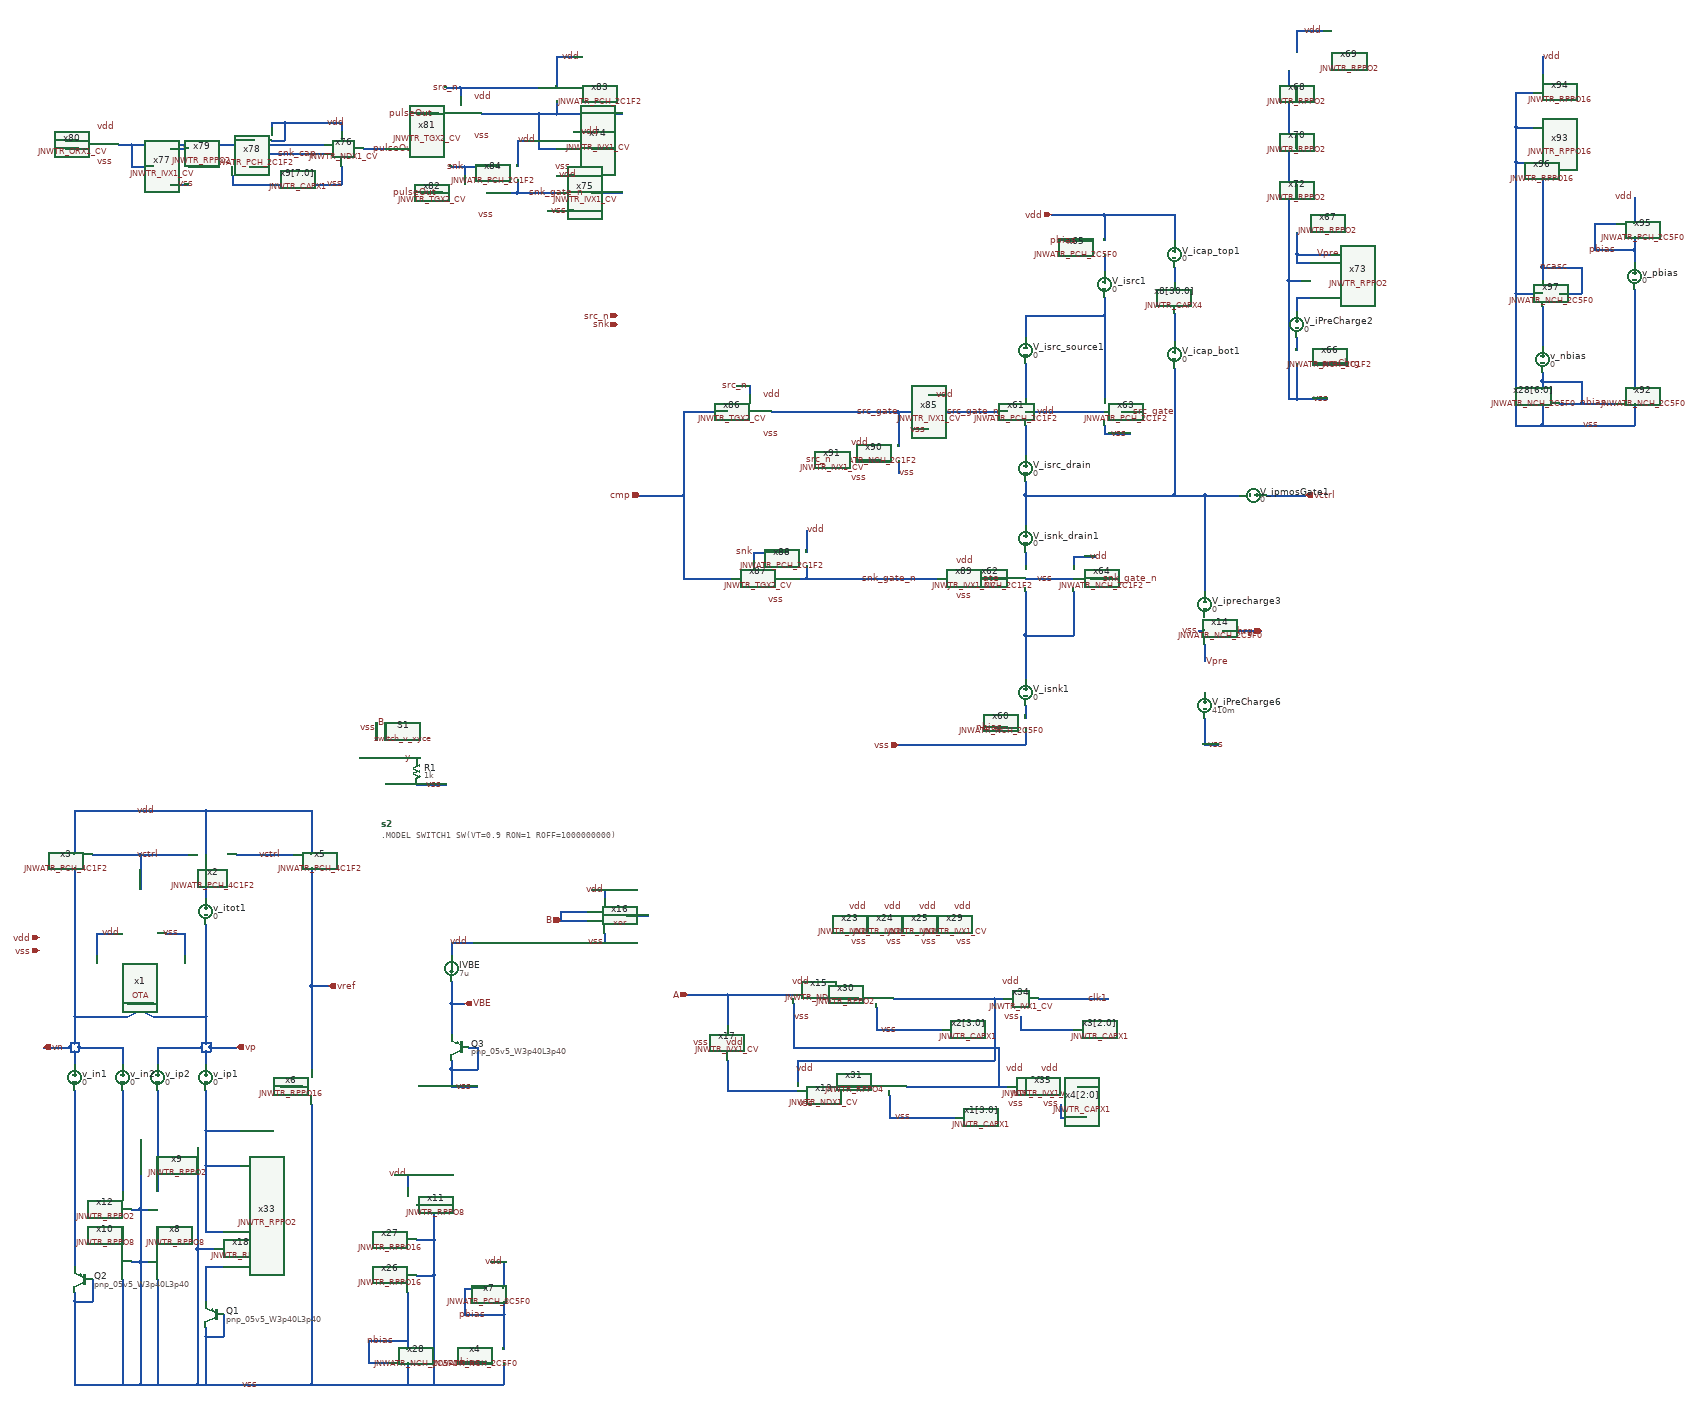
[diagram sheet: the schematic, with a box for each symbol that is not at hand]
v {xschem version=3.4.6 file_version=1.2}
G {}
K {}
V {}
S {}
E {}
N 870 -120 960 -120 {
lab=nbias}
N 960 -120 960 -100 {
lab=nbias}
N 1180 -210 1180 -180 {
lab=pbias}
N 1090 -180 1180 -180 {
lab=pbias}
N 1090 -240 1090 -180 {
lab=pbias}
N 1090 -240 1140 -240 {
lab=pbias}
N 1180 -300 1180 -240 {
lab=vdd}
N 960 -70 960 -20 {
lab=vss}
N 930 -500 960 -500 {
lab=vdd}
N 1020 -270 1020 -20 {
lab=vss}
N 980 -270 1020 -270 {
lab=vss}
N 1020 -350 1020 -270 {
lab=vss}
N 980 -350 1020 -350 {
lab=vss}
N 1020 -430 1020 -350 {
lab=vss}
N 980 -430 1020 -430 {
lab=vss}
N 960 -500 960 -470 {
lab=vdd}
N 1090 -70 1140 -70 {
lab=nbias}
N 1020 -20 1180 -20 {
lab=vss}
N 1150 -300 1180 -300 {
lab=vdd}
N 870 -120 870 -70 {
lab=nbias}
N 870 -70 920 -70 {
lab=nbias}
N 1180 -70 1180 -20 {
lab=vss}
N 1180 -180 1180 -100 {
lab=pbias}
N 960 -230 960 -120 {
lab=nbias}
N 490 -790 490 -780 {
lab=vp}
N 500 -800 510 -800 {
lab=vp}
N 210 -790 210 -780 {
lab=vn}
N 200 -800 210 -800 {
lab=vn}
N 510 -790 510 -780 {
lab=vp}
N 210 -800 210 -790 {
lab=vn}
N 490 -800 490 -790 {
lab=vp}
N 390 -790 490 -790 {
lab=vp}
N 200 -780 210 -780 {
lab=vn}
N 210 -790 310 -790 {
lab=vn}
N 190 -790 190 -780 {
lab=vn}
N 240 -260 240 -210 {
lab=vss}
N 200 -210 240 -210 {
lab=vss}
N 200 -230 200 -210 {
lab=vss}
N 540 -180 540 -130 {
lab=vss}
N 500 -130 540 -130 {
lab=vss}
N 500 -150 500 -130 {
lab=vss}
N 500 -780 510 -780 {
lab=vp}
N 380 -860 500 -860 {
lab=vp}
N 200 -860 200 -800 {
lab=vn}
N 190 -800 200 -800 {
lab=vn}
N 500 -860 500 -800 {
lab=vp}
N 490 -800 500 -800 {
lab=vp}
N 200 -1200 200 -860 {
lab=vn}
N 200 -860 320 -860 {
lab=vn}
N 350 -1230 350 -1150 {
lab=vctrl}
N 350 -1230 460 -1230 {
lab=vctrl}
N 240 -1230 350 -1230 {
lab=vctrl}
N 200 -1330 200 -1230 {
lab=vdd}
N 200 -1330 500 -1330 {
lab=vdd}
N 740 -1330 740 -1230 {
lab=vdd}
N 500 -1330 740 -1330 {
lab=vdd}
N 500 -1330 500 -1230 {
lab=vdd}
N 740 -930 740 -740 {
lab=vref}
N 510 -790 570 -790 {
lab=vp}
N 510 -800 510 -790 {
lab=vp}
N 130 -790 190 -790 {
lab=vn}
N 190 -800 190 -790 {
lab=vn}
N 740 -930 780 -930 {
lab=vref}
N 740 -1200 740 -930 {
lab=vref}
N 570 -1230 700 -1230 {
lab=vctrl}
N 500 -130 500 -20 {
lab=vss}
N 200 -210 200 -20 {
lab=vss}
N 500 -20 740 -20 {
lab=vss}
N 670 -700 720 -700 {
lab=vss}
N 740 -660 740 -20 {
lab=vss}
N 960 -20 1020 -20 {
lab=vss}
N 740 -20 960 -20 {
lab=vss}
N 480 -20 500 -20 {
lab=vss}
N 500 -1200 500 -1130 {
lab=#net1}
N 500 -780 500 -750 {
lab=vp}
N 490 -780 500 -780 {
lab=vp}
N 390 -790 390 -750 {
lab=vp}
N 200 -780 200 -750 {
lab=vn}
N 190 -780 200 -780 {
lab=vn}
N 200 -690 200 -290 {
lab=#net2}
N 310 -790 310 -750 {
lab=vn}
N 1060 -890 1060 -820 {
lab=VBE}
N 1060 -740 1060 -700 {
lab=vss}
N 1060 -700 1120 -700 {
lab=vss}
N 1060 -1030 1060 -1000 {
lab=vdd}
N 1060 -1030 1110 -1030 {
lab=vdd}
N 1060 -890 1090 -890 {
lab=VBE}
N 1060 -940 1060 -890 {
lab=VBE}
N 1100 -790 1120 -790 {
lab=vss}
N 1120 -790 1120 -740 {
lab=vss}
N 1060 -740 1120 -740 {
lab=vss}
N 1060 -760 1060 -740 {
lab=vss}
N 1310 -1100 1370 -1100 {
lab=B}
N 1310 -1080 1370 -1080 {
lab=B}
N 1410 -1150 1410 -1130 {
lab=vdd}
N 1380 -1150 1410 -1150 {
lab=vdd}
N 1410 -1050 1410 -1030 {
lab=vss}
N 1380 -1030 1410 -1030 {
lab=vss}
N 1460 -1090 1510 -1090 {
lab=#net3}
N 500 -520 500 -370 {
lab=#net4}
N 350 -300 370 -300 {
lab=vss}
N 330 -300 350 -300 {
lab=vss}
N 350 -420 370 -420 {
lab=vss}
N 330 -420 350 -420 {
lab=vss}
N 350 -420 350 -300 {
lab=vss}
N 350 -580 350 -420 {
lab=vss}
N 500 -520 580 -520 {
lab=#net4}
N 500 -600 580 -600 {
lab=#net4}
N 310 -690 310 -460 {
lab=#net5}
N 390 -690 390 -460 {
lab=#net6}
N 500 -690 500 -600 {
lab=#net4}
N 500 -290 500 -210 {
lab=#net7}
N 480 -330 480 -20 {
lab=vss}
N 390 -20 480 -20 {
lab=vss}
N 350 -300 350 -20 {
lab=vss}
N 310 -260 310 -20 {
lab=vss}
N 200 -20 310 -20 {
lab=vss}
N 390 -260 390 -20 {
lab=vss}
N 350 -20 390 -20 {
lab=vss}
N 310 -20 350 -20 {
lab=vss}
N 500 -1070 500 -860 {
lab=vp}
N 320 -860 380 -890 {
lab=vn}
N 320 -890 380 -860 {
lab=vp}
N 250 -1050 250 -1000 {
lab=vdd}
N 250 -1050 290 -1050 {
lab=vdd}
N 450 -1050 450 -1000 {
lab=vss}
N 410 -1050 450 -1050 {
lab=vss}
N 940 -1450 980 -1450 {
lab=y}
N 890 -1530 890 -1490 {
lab=vss}
N 910 -1530 910 -1490 {
lab=B}
N 850 -1450 880 -1450 {
lab=#net8}
N 980 -1390 1050 -1390 {
lab=vss}
N 1690 -760 1690 -690 {
lab=#net9}
N 1690 -690 1850 -690 {
lab=#net9}
N 1690 -910 1840 -910 {
lab=A}
N 1690 -910 1690 -840 {
lab=A}
N 1600 -910 1690 -910 {
lab=A}
N 1940 -700 2020 -700 {
lab=#net10}
N 2310 -790 2310 -700 {
lab=#net11}
N 1840 -790 2310 -790 {
lab=#net11}
N 1840 -890 1840 -790 {
lab=#net11}
N 1930 -900 1990 -900 {
lab=#net12}
N 2300 -900 2300 -760 {
lab=#net13}
N 1850 -760 2300 -760 {
lab=#net13}
N 1850 -760 1850 -710 {
lab=#net13}
N 1310 -1100 1310 -1080 {
lab=B}
N 2300 -900 2320 -900 {
lab=#net13}
N 2060 -680 2060 -630 {
lab=vss}
N 2100 -700 2310 -700 {
lab=#net11}
N 2060 -630 2210 -630 {
lab=vss}
N 2030 -880 2030 -830 {
lab=vss}
N 2070 -900 2300 -900 {
lab=#net13}
N 2030 -830 2180 -830 {
lab=vss}
N 2310 -700 2330 -700 {
lab=#net11}
N 2400 -900 2560 -900 {
lab=clk1}
N 2490 -700 2530 -700 {
lab=clk2}
N 2450 -660 2450 -630 {
lab=vss}
N 2450 -630 2510 -630 {
lab=vss}
N 2360 -860 2360 -830 {
lab=vss}
N 2360 -830 2480 -830 {
lab=vss}
N 480 -330 520 -330 {lab=vss}
N 480 -560 480 -330 {
lab=vss}
N 500 -370 540 -370 {lab=#net4}
N 500 -290 540 -290 {lab=#net7}
N 500 -600 500 -520 {lab=#net4}
N 390 -380 390 -340 {lab=#net14}
N 310 -380 310 -340 {lab=#net15}
N 570 -2850 770 -2850 {
lab=#net15}
N 810 -2900 810 -2880 {
lab=vdd}
N 810 -2800 810 -2760 {
lab=vss}
N 330 -2850 330 -2800 {
lab=#net15}
N 620 -2830 620 -2800 {
lab=snk_cap}
N 620 -2830 770 -2830 {
lab=snk_cap}
N 560 -2780 560 -2760 {
lab=vss}
N 600 -2800 620 -2800 {
lab=snk_cap}
N 1300 -2920 1450 -2920 {
lab=#net16}
N 1335 -2800 1340 -2800 {
lab=vss}
N 1340 -2880 1355 -2880 {
lab=vdd}
N 1260 -2920 1260 -2840 {
lab=#net16}
N 1260 -2840 1300 -2840 {
lab=#net16}
N 1380 -2840 1430 -2840 {
lab=#net17}
N 1380 -2740 1450 -2740 {
lab=#net18}
N 1300 -2780 1340 -2780 {
lab=vdd}
N 460 -2800 520 -2800 {
lab=#net19}
N 330 -2800 380 -2800 {
lab=#net15}
N 420 -2760 460 -2760 {
lab=vss}
N 420 -2840 460 -2840 {
lab=vdd}
N 560 -2760 810 -2760 {
lab=vss}
N 1280 -2700 1340 -2700 {
lab=vss}
N 300 -2850 330 -2850 {
lab=#net15}
N 650 -2900 650 -2890 {
lab=vdd}
N 680 -2900 810 -2900 {
lab=vdd}
N 570 -2860 610 -2860 {
lab=#net15}
N 570 -2860 570 -2850 {
lab=#net15}
N 330 -2850 570 -2850 {
lab=#net15}
N 650 -2860 680 -2860 {
lab=vdd}
N 680 -2900 680 -2860 {
lab=vdd}
N 650 -2900 680 -2900 {
lab=vdd}
N 180 -2840 210 -2840 {lab=#net20}
N 180 -2860 210 -2860 {lab=#net21}
N 860 -2840 910 -2840 {lab=pulseOut}
N 1080 -2980 1080 -2960 {lab=src_n}
N 1050 -2980 1080 -2980 {lab=src_n}
N 1130 -2920 1260 -2920 {lab=#net16}
N 980 -2920 1030 -2920 {lab=pulseOut}
N 1300 -2950 1300 -2920 {lab=#net16}
N 1260 -2920 1300 -2920 {
lab=#net16}
N 1300 -3050 1300 -2980 {lab=vdd}
N 1300 -3050 1340 -3050 {lab=vdd}
N 1080 -2980 1260 -2980 {lab=src_n}
N 1090 -2800 1090 -2780 {lab=snk}
N 1060 -2800 1090 -2800 {lab=snk}
N 990 -2740 1040 -2740 {lab=pulseOut}
N 1210 -2740 1300 -2740 {lab=snk_gate_n}
N 1090 -2800 1170 -2800 {lab=snk}
N 1210 -2860 1210 -2800 {lab=vdd}
N 1210 -2860 1230 -2860 {lab=vdd}
N 1210 -2770 1210 -2740 {lab=snk_gate_n}
N 1140 -2740 1210 -2740 {lab=snk_gate_n}
N 2430 -2690 2550 -2690 {
lab=vdd}
N 2550 -2690 2550 -2630 {
lab=vdd}
N 2370 -1520 2370 -1480 {
lab=vss}
N 2460 -2630 2510 -2630 {
lab=pbias}
N 2300 -1520 2330 -1520 {
lab=nbias}
N 2990 -2600 3070 -2600 {
lab=Vpre}
N 2550 -2210 2550 -2190 {
lab=vss}
N 2550 -2190 2610 -2190 {
lab=vss}
N 2590 -2240 2615 -2240 {
lab=src_gate}
N 2480 -1910 2480 -1890 {
lab=vdd}
N 2480 -1910 2530 -1910 {
lab=vdd}
N 2520 -1860 2570 -1860 {
lab=snk_gate_n}
N 2370 -1570 2370 -1540 {
lab=#net1}
N 2550 -2600 2550 -2560 {
lab=#net2}
N 2990 -2350 2990 -2270 {
lab=vss}
N 3030 -2350 3100 -2350 {
lab=preChrg}
N 2990 -2410 2990 -2380 {
lab=#net3}
N 2990 -2500 2990 -2470 {
lab=#net4}
N 2990 -2270 3060 -2270 {
lab=vss}
N 2970 -2270 2990 -2270 {
lab=vss}
N 2990 -2980 2990 -2950 {
lab=#net5}
N 2990 -3110 2990 -3060 {
lab=vdd}
N 2990 -3110 3050 -3110 {
lab=vdd}
N 2990 -2870 2990 -2840 {
lab=#net6}
N 2370 -2460 2550 -2460 {
lab=#net7}
N 2550 -2500 2550 -2460 {
lab=#net7}
N 2080 -1480 2370 -1480 {
lab=vss}
N 2550 -2690 2710 -2690 {
lab=vdd}
N 2370 -2240 2550 -2240 {
lab=vdd}
N 2370 -1860 2480 -1860 {
lab=vss}
N 2370 -1730 2370 -1630 {
lab=#net8}
N 2480 -1830 2480 -1730 {
lab=#net8}
N 2370 -1730 2480 -1730 {
lab=#net8}
N 2370 -1830 2370 -1730 {
lab=#net8}
N 2550 -2460 2550 -2270 {
lab=#net7}
N 2710 -2465 2710 -2400 {
lab=#net9}
N 2710 -2340 2710 -2050 {
lab=#net10}
N 2780 -2050 2860 -2050 {
lab=#net10}
N 2920 -2050 3010 -2050 {
lab=vctrl}
N 2710 -2570 2710 -2535 {
lab=#net11}
N 2710 -2690 2710 -2630 {
lab=vdd}
N 2370 -2460 2370 -2410 {
lab=#net7}
N 2370 -2350 2370 -2270 {
lab=#net12}
N 2820 -1740 2910 -1740 {
lab=preChrg}
N 2765 -1740 2780 -1740 {
lab=vss}
N 2990 -2600 2990 -2580 {lab=Vpre}
N 2970 -2540 2970 -2270 {
lab=vss}
N 2990 -2580 3020 -2580 {lab=Vpre}
N 2990 -2500 3020 -2500 {lab=#net4}
N 2970 -2540 3000 -2540 {lab=vss}
N 2990 -2650 2990 -2600 {lab=Vpre}
N 2990 -2760 2990 -2730 {lab=#net13}
N 2970 -3020 2970 -2540 {
lab=vss}
N 2780 -1540 2780 -1480 {lab=vss}
N 2780 -1480 2810 -1480 {lab=vss}
N 1490 -2050 1590 -2050 {lab=cmp}
N 2145 -2200 2150 -2200 {
lab=vss}
N 2150 -2280 2165 -2280 {
lab=vdd}
N 1740 -2300 1740 -2280 {lab=src_n}
N 1710 -2300 1740 -2300 {lab=src_n}
N 2080 -2240 2110 -2240 {lab=src_gate}
N 1750 -1920 1750 -1900 {lab=snk}
N 1870 -1860 2170 -1860 {lab=snk_gate_n}
N 2080 -2130 2080 -2100 {lab=vss}
N 2010 -2130 2040 -2130 {lab=#net14}
N 3550 -2310 3640 -2310 {
lab=nbias}
N 3550 -2310 3550 -2290 {
lab=nbias}
N 3760 -2640 3760 -2610 {
lab=pbias}
N 3670 -2610 3760 -2610 {
lab=pbias}
N 3670 -2670 3670 -2610 {
lab=pbias}
N 3670 -2670 3720 -2670 {
lab=pbias}
N 3760 -2730 3760 -2670 {
lab=vdd}
N 3550 -2260 3550 -2210 {
lab=vss}
N 3490 -2210 3550 -2210 {
lab=vss}
N 3640 -2310 3640 -2260 {
lab=nbias}
N 3590 -2260 3640 -2260 {
lab=nbias}
N 3760 -2260 3760 -2210 {
lab=vss}
N 3640 -2260 3720 -2260 {
lab=nbias}
N 3760 -2610 3760 -2580 {
lab=pbias}
N 3490 -2810 3530 -2810 {
lab=vss}
N 3550 -3050 3550 -3010 {
lab=vdd}
N 3490 -2890 3490 -2810 {
lab=vss}
N 3490 -2510 3490 -2210 {
lab=vss}
N 3550 -2210 3760 -2210 {
lab=vss}
N 3490 -2890 3530 -2890 {
lab=vss}
N 3490 -2970 3490 -2890 {
lab=vss}
N 3550 -2330 3550 -2310 {lab=nbias}
N 3760 -2520 3760 -2290 {lab=#net15}
N 3550 -2770 3550 -2570 {lab=ncasc}
N 3550 -2570 3640 -2570 {lab=ncasc}
N 3640 -2570 3640 -2510 {lab=ncasc}
N 3550 -2570 3550 -2540 {lab=ncasc}
N 3590 -2510 3640 -2510 {lab=ncasc}
N 3550 -2480 3550 -2390 {lab=#net16}
N 3490 -2970 3530 -2970 {lab=vss}
N 3490 -2510 3550 -2510 {lab=vss}
N 3490 -2810 3490 -2510 {
lab=vss}
N 2780 -1710 2780 -1670 {lab=Vpre}
N 2190 -2240 2330 -2240 {lab=src_gate_n}
N 1590 -2050 1590 -1860 {lab=cmp}
N 1590 -2240 1690 -2240 {lab=cmp}
N 1590 -1860 1700 -1860 {lab=cmp}
N 1590 -2240 1590 -2050 {lab=cmp}
N 1870 -1890 1870 -1860 {lab=snk_gate_n}
N 1800 -1860 1870 -1860 {lab=snk_gate_n}
N 1750 -1920 1830 -1920 {lab=snk}
N 2080 -2240 2080 -2160 {lab=src_gate}
N 1790 -2240 2080 -2240 {lab=src_gate}
N 1870 -1970 1870 -1920 {lab=vdd}
N 2370 -1920 2370 -1890 {lab=#net17}
N 2370 -2050 2370 -1980 {lab=#net10}
N 2370 -2080 2370 -2050 {lab=#net10}
N 2370 -2210 2370 -2140 {lab=#net18}
N 2780 -2050 2780 -1830 {lab=#net10}
N 2710 -2050 2780 -2050 {
lab=#net10}
N 2370 -2050 2710 -2050 {
lab=#net10}
N 2250 -1860 2330 -1860 {lab=snk_gate}
C {devices/ipin.sym} 120 -1010 0 0 {name=p4 lab=vss}
C {devices/ipin.sym} 120 -1040 0 0 {name=p5 lab=vdd}
C {devices/lab_wire.sym} 1140 -180 0 0 {name=p32 sig_type=std_logic lab=pbias}
C {devices/lab_wire.sym} 960 -500 0 0 {name=p34 sig_type=std_logic lab=vdd}
C {JNW_ATR_SKY130A/JNWATR_PCH_8C5F0.sym} 1140 -240 0 0 {name=x7 }
C {JNW_ATR_SKY130A/JNWATR_NCH_2C5F0.sym} 920 -70 0 0 {name=x28 }
C {devices/lab_wire.sym} 930 -120 0 0 {name=p12 sig_type=std_logic lab=nbias}
C {devices/lab_wire.sym} 1180 -300 0 0 {name=p13 sig_type=std_logic lab=vdd}
C {JNW_ATR_SKY130A/JNWATR_NCH_2C5F0.sym} 1140 -70 0 0 {name=x4 }
C {devices/lab_wire.sym} 1130 -70 0 0 {name=p14 sig_type=std_logic lab=nbias}
C {JNW_TR_SKY130A/JNWTR_RPPO16.sym} 960 -230 3 0 {name=x26 }
C {JNW_TR_SKY130A/JNWTR_RPPO16.sym} 960 -310 3 0 {name=x27 }
C {JNW_TR_SKY130A/JNWTR_RPPO8.sym} 960 -390 3 0 {name=x11 }
C {sky130_fd_pr/pnp_05v5.sym} 520 -180 0 1 {name=Q1
model=pnp_05v5_W3p40L3p40
m=8
spiceprefix=X
}
C {sky130_fd_pr/pnp_05v5.sym} 220 -260 0 1 {name=Q2
model=pnp_05v5_W3p40L3p40
m=1
spiceprefix=X
}
C {devices/lab_wire.sym} 340 -1330 0 1 {name=p29 sig_type=std_logic lab=vdd

}
C {devices/opin.sym} 130 -790 2 0 {name=p44 lab=vn}
C {JNW_ATR_SKY130A/JNWATR_PCH_4C1F2.sym} 460 -1230 0 0 {name=x2 }
C {JNW_ATR_SKY130A/JNWATR_PCH_4C1F2.sym} 240 -1230 0 1 {name=x3 }
C {JNW_ATR_SKY130A/JNWATR_PCH_4C1F2.sym} 700 -1230 0 0 {name=x5 }
C {devices/lab_wire.sym} 340 -1230 0 1 {name=p8 sig_type=std_logic lab=vctrl

}
C {devices/lab_wire.sym} 620 -1230 0 1 {name=p9 sig_type=std_logic lab=vctrl

}
C {devices/lab_wire.sym} 620 -20 0 0 {name=p3 sig_type=std_logic lab=vss
}
C {devices/opin.sym} 570 -790 0 0 {name=p7 lab=vp}
C {devices/opin.sym} 780 -930 0 0 {name=p10 lab=vref}
C {devices/lab_wire.sym} 700 -700 0 0 {name=p11 sig_type=std_logic lab=vss
}
C {JNW_TR_SKY130A/JNWTR_RPPO16.sym} 740 -740 1 0 {name=x6 }
C {devices/vsource.sym} 500 -1100 0 0 {name=v_itot1 value=0 savecurrent=true}
C {devices/vsource.sym} 500 -720 0 0 {name=v_ip1 value=0 savecurrent=true}
C {devices/vsource.sym} 390 -720 0 0 {name=v_ip2 value=0 savecurrent=true}
C {devices/vsource.sym} 200 -720 0 0 {name=v_in1 value=0 savecurrent=true}
C {devices/vsource.sym} 310 -720 0 0 {name=v_in2 value=0 savecurrent=true}
C {devices/isource.sym} 1060 -970 0 0 {name=IVBE value=7u}
C {devices/lab_wire.sym} 1100 -1030 0 0 {name=p15 sig_type=std_logic lab=vdd}
C {devices/lab_wire.sym} 1110 -700 0 0 {name=p16 sig_type=std_logic lab=vss
}
C {devices/opin.sym} 1090 -890 0 0 {name=p17 lab=VBE}
C {sky130_fd_pr/pnp_05v5.sym} 1080 -790 0 1 {name=Q3
model=pnp_05v5_W3p40L3p40
m=1
spiceprefix=X
}
C {devices/ipin.sym} 1310 -1080 0 0 {name=p18 lab=B}
C {JNW_AVV_SKY130A/xor.sym} 1410 -1090 0 0 {name=x16}
C {devices/lab_wire.sym} 1410 -1150 0 0 {name=p20 sig_type=std_logic lab=vdd}
C {devices/lab_wire.sym} 1410 -1030 0 0 {name=p21 sig_type=std_logic lab=vss
}
C {JNW_TR_SKY130A/JNWTR_RPPO2.sym} 500 -370 1 0 {name=x18 }
C {JNW_AVV_SKY130A/OTA.sym} 350 -1000 3 0 {name=x1}
C {devices/lab_wire.sym} 260 -1050 0 1 {name=p1 sig_type=std_logic lab=vdd

}
C {devices/lab_wire.sym} 440 -1050 0 0 {name=p2 sig_type=std_logic lab=vss
}
C {devices/lab_wire.sym} 890 -1520 0 0 {name=p6 sig_type=std_logic lab=vss
}
C {devices/lab_wire.sym} 910 -1530 0 0 {name=p24 sig_type=std_logic lab=B
}
C {devices/lab_wire.sym} 970 -1450 0 0 {name=p25 sig_type=std_logic lab=y
}
C {devices/switch_v_xyce.sym} 910 -1450 1 0 {.MODEL SWITCH1 SW(VT=0.5 VH=0.01 RON=0.01 ROFF=10000000)

name=S1 model=SWITCH1 state=OFF

}
C {devices/netlist.sym} 900 -1300 0 0 {name=s2 value=".MODEL SWITCH1 SW(VT=0.9 RON=1 ROFF=1000000000)"
}
C {devices/res.sym} 980 -1420 0 0 {name=R1
value=1k
footprint=1206
device=resistor
m=1}
C {devices/lab_wire.sym} 1040 -1390 0 0 {name=p22 sig_type=std_logic lab=vss
}
C {JNW_TR_SKY130A/JNWTR_NDX1_CV.sym} 1850 -690 0 0 {name=x13 }
C {devices/lab_wire.sym} 1890 -740 0 0 {name=p26 sig_type=std_logic lab=vdd}
C {devices/lab_wire.sym} 1890 -660 0 0 {name=p27 sig_type=std_logic lab=vss
}
C {JNW_TR_SKY130A/JNWTR_NDX1_CV.sym} 1840 -890 0 0 {name=x15 }
C {devices/lab_wire.sym} 1880 -940 0 0 {name=p28 sig_type=std_logic lab=vdd}
C {devices/lab_wire.sym} 1880 -860 0 0 {name=p30 sig_type=std_logic lab=vss
}
C {JNW_TR_SKY130A/JNWTR_IVX1_CV.sym} 1690 -840 1 0 {name=x17 }
C {devices/lab_wire.sym} 1650 -800 0 0 {name=p31 sig_type=std_logic lab=vss
}
C {devices/lab_wire.sym} 1730 -800 0 0 {name=p33 sig_type=std_logic lab=vdd}
C {devices/ipin.sym} 1600 -910 0 0 {name=p35 lab=A}
C {JNW_TR_SKY130A/JNWTR_IVX1_CV.sym} 1970 -1070 0 0 {name=x23 }
C {devices/lab_wire.sym} 2010 -1030 3 0 {name=p36 sig_type=std_logic lab=vss
}
C {devices/lab_wire.sym} 2010 -1110 3 0 {name=p37 sig_type=std_logic lab=vdd}
C {JNW_TR_SKY130A/JNWTR_IVX1_CV.sym} 2050 -1070 0 0 {name=x24 }
C {devices/lab_wire.sym} 2090 -1030 3 0 {name=p38 sig_type=std_logic lab=vss
}
C {devices/lab_wire.sym} 2090 -1110 3 0 {name=p39 sig_type=std_logic lab=vdd}
C {JNW_TR_SKY130A/JNWTR_IVX1_CV.sym} 2130 -1070 0 0 {name=x25 }
C {devices/lab_wire.sym} 2170 -1030 3 0 {name=p40 sig_type=std_logic lab=vss
}
C {devices/lab_wire.sym} 2170 -1110 3 0 {name=p41 sig_type=std_logic lab=vdd}
C {JNW_TR_SKY130A/JNWTR_IVX1_CV.sym} 2210 -1070 0 0 {name=x29 }
C {devices/lab_wire.sym} 2250 -1030 3 0 {name=p42 sig_type=std_logic lab=vss
}
C {devices/lab_wire.sym} 2250 -1110 3 0 {name=p43 sig_type=std_logic lab=vdd}
C {devices/lab_wire.sym} 2560 -900 0 0 {name=p53 sig_type=std_logic lab=clk1}
C {devices/lab_wire.sym} 2530 -700 0 0 {name=p54 sig_type=std_logic lab=clk2}
C {JNW_TR_SKY130A/JNWTR_IVX1_CV.sym} 2320 -900 0 0 {name=x34 }
C {devices/lab_wire.sym} 2360 -860 3 0 {name=p19 sig_type=std_logic lab=vss
}
C {devices/lab_wire.sym} 2360 -940 3 0 {name=p23 sig_type=std_logic lab=vdd}
C {JNW_TR_SKY130A/JNWTR_CAPX1.sym} 2210 -640 0 0 {name=x1[3:0]}
C {devices/lab_wire.sym} 2110 -630 3 0 {name=p45 sig_type=std_logic lab=vss
}
C {JNW_TR_SKY130A/JNWTR_CAPX1.sym} 2180 -840 0 0 {name=x2[3:0]}
C {devices/lab_wire.sym} 2080 -830 3 0 {name=p46 sig_type=std_logic lab=vss
}
C {JNW_TR_SKY130A/JNWTR_IVX1_CV.sym} 2330 -700 0 0 {name=x32 }
C {devices/lab_wire.sym} 2370 -660 3 0 {name=p47 sig_type=std_logic lab=vss
}
C {devices/lab_wire.sym} 2370 -740 3 0 {name=p48 sig_type=std_logic lab=vdd}
C {JNW_TR_SKY130A/JNWTR_IVX1_CV.sym} 2410 -700 0 0 {name=x35 }
C {devices/lab_wire.sym} 2450 -660 3 0 {name=p51 sig_type=std_logic lab=vss
}
C {devices/lab_wire.sym} 2450 -740 3 0 {name=p52 sig_type=std_logic lab=vdd}
C {JNW_TR_SKY130A/JNWTR_CAPX1.sym} 2480 -840 0 0 {name=x3[2:0]}
C {JNW_TR_SKY130A/JNWTR_CAPX1.sym} 2510 -640 0 0 {name=x4[2:0]}
C {JNW_TR_SKY130A/JNWTR_RPPO4.sym} 2020 -700 0 0 {name=x31 }
C {JNW_TR_SKY130A/JNWTR_RPPO2.sym} 1990 -900 0 0 {name=x30 }
C {JNW_TR_SKY130A/JNWTR_RPPO2.sym} 540 -370 1 0 {name=x33 }
C {JNW_TR_SKY130A/JNWTR_RPPO8.sym} 390 -340 1 0 {name=x8 }
C {JNW_TR_SKY130A/JNWTR_RPPO2.sym} 390 -460 1 0 {name=x9 }
C {JNW_TR_SKY130A/JNWTR_RPPO8.sym} 310 -340 3 1 {name=x10 }
C {JNW_TR_SKY130A/JNWTR_RPPO2.sym} 310 -460 3 1 {name=x12 }
C {devices/lab_wire.sym} 775 -2900 0 1 {name=p130 sig_type=std_logic lab=vdd}
C {devices/lab_wire.sym} 775 -2760 0 1 {name=p131 sig_type=std_logic lab=vss}
C {JNW_TR_SKY130A/JNWTR_CAPX1.sym} 710 -2770 0 0 {name=x9[7:0]}
C {devices/lab_wire.sym} 755 -2830 0 0 {name=p134 sig_type=std_logic lab=snk_cap}
C {JNW_TR_SKY130A/JNWTR_IVX1_CV.sym} 1300 -2840 0 0 {name=x74 }
C {devices/lab_wire.sym} 1355 -2880 0 1 {name=p135 sig_type=std_logic lab=vdd}
C {devices/lab_wire.sym} 1335 -2800 0 0 {name=p136 sig_type=std_logic lab=vss}
C {JNW_TR_SKY130A/JNWTR_IVX1_CV.sym} 1300 -2740 0 0 {name=x75 }
C {devices/lab_wire.sym} 1235 -2740 0 1 {name=p137 sig_type=std_logic lab=snk_gate_n}
C {JNW_TR_SKY130A/JNWTR_NDX1_CV.sym} 770 -2830 0 0 {name=x76 }
C {devices/lab_wire.sym} 1325 -2700 0 0 {name=p138 sig_type=std_logic lab=vss}
C {devices/lab_wire.sym} 1305 -2780 0 1 {name=p139 sig_type=std_logic lab=vdd}
C {JNW_TR_SKY130A/JNWTR_IVX1_CV.sym} 380 -2800 0 0 {name=x77 }
C {devices/lab_wire.sym} 435 -2760 0 1 {name=p140 sig_type=std_logic lab=vss}
C {devices/lab_wire.sym} 445 -2840 0 1 {name=p141 sig_type=std_logic lab=vdd}
C {JNW_ATR_SKY130A/JNWATR_PCH_2C1F2.sym} 610 -2860 0 0 {name=x78 }
C {JNW_TR_SKY130A/JNWTR_RPPO2.sym} 520 -2800 0 0 {name=x79 }
C {JNW_TR_SKY130A/JNWTR_ORX1_CV.sym} 210 -2840 0 0 {name=x80 }
C {devices/lab_wire.sym} 250 -2890 0 1 {name=p142 sig_type=std_logic lab=vdd

}
C {devices/lab_wire.sym} 250 -2810 0 1 {name=p143 sig_type=std_logic lab=vss

}
C {devices/lab_wire.sym} 880 -2840 0 1 {name=p144 sig_type=std_logic lab=pulseOut

}
C {JNW_TR_SKY130A/JNWTR_TGX2_CV.sym} 1020 -2920 0 0 {name=x81 }
C {devices/lab_wire.sym} 1110 -2960 0 1 {name=p145 sig_type=std_logic lab=vdd

}
C {devices/lab_wire.sym} 1110 -2870 0 1 {name=p146 sig_type=std_logic lab=vss

}
C {devices/lab_wire.sym} 1080 -2980 0 0 {name=p147 sig_type=std_logic lab=src_n

}
C {devices/lab_wire.sym} 1020 -2920 0 0 {name=p148 sig_type=std_logic lab=pulseOut

}
C {devices/lab_wire.sym} 1310 -3050 0 1 {name=p149 sig_type=std_logic lab=vdd

}
C {JNW_TR_SKY130A/JNWTR_TGX2_CV.sym} 1030 -2740 0 0 {name=x82 }
C {devices/lab_wire.sym} 1120 -2780 0 1 {name=p150 sig_type=std_logic lab=vdd

}
C {devices/lab_wire.sym} 1120 -2690 0 1 {name=p151 sig_type=std_logic lab=vss

}
C {devices/lab_wire.sym} 1090 -2800 0 0 {name=p152 sig_type=std_logic lab=snk

}
C {devices/lab_wire.sym} 1030 -2740 0 0 {name=p153 sig_type=std_logic lab=pulseOut

}
C {JNW_ATR_SKY130A/JNWATR_PCH_2C1F2.sym} 1260 -2980 0 0 {name=x83 }
C {JNW_ATR_SKY130A/JNWATR_PCH_2C1F2.sym} 1170 -2800 0 0 {name=x84 }
C {devices/lab_wire.sym} 1210 -2860 0 1 {name=p154 sig_type=std_logic lab=vdd

}
C {devices/ipin.sym} 2430 -2690 0 0 {name=p113 lab=vdd}
C {devices/opin.sym} 3010 -2050 0 0 {name=p114 lab=vctrl}
C {devices/ipin.sym} 2080 -1480 0 0 {name=p115 lab=vss
}
C {JNW_TR_SKY130A/JNWTR_CAPX4.sym} 2710 -2475 0 0 {name=x8[30:0]}
C {devices/ipin.sym} 2910 -1740 2 0 {name=p116 lab=preChrg
}
C {devices/lab_wire.sym} 3005 -3110 0 1 {name=p117 sig_type=std_logic lab=vdd}
C {JNW_ATR_SKY130A/JNWATR_NCH_2C5F0.sym} 2330 -1520 0 0 {name=x60 }
C {devices/lab_wire.sym} 2395 -2240 0 1 {name=p118 sig_type=std_logic lab=vdd}
C {devices/lab_wire.sym} 3025 -2270 0 1 {name=p119 sig_type=std_logic lab=vss}
C {devices/lab_wire.sym} 3035 -2600 0 1 {name=p120 sig_type=std_logic lab=Vpre}
C {JNW_ATR_SKY130A/JNWATR_PCH_2C1F2.sym} 2330 -2240 0 0 {name=x61 }
C {JNW_ATR_SKY130A/JNWATR_NCH_2C1F2.sym} 2330 -1860 0 0 {name=x62 }
C {JNW_ATR_SKY130A/JNWATR_PCH_2C1F2.sym} 2590 -2240 0 1 {name=x63 }
C {devices/lab_wire.sym} 2605 -2190 0 0 {name=p121 sig_type=std_logic lab=vss}
C {devices/lab_wire.sym} 2615 -2240 0 1 {name=p122 sig_type=std_logic lab=src_gate}
C {JNW_ATR_SKY130A/JNWATR_NCH_2C1F2.sym} 2520 -1860 0 1 {name=x64 }
C {devices/lab_wire.sym} 2435 -1860 0 0 {name=p123 sig_type=std_logic lab=vss}
C {devices/lab_wire.sym} 2545 -1860 0 1 {name=p124 sig_type=std_logic lab=snk_gate_n}
C {devices/vsource.sym} 2550 -2530 0 0 {name=V_isrc1 value=0 savecurrent=true}
C {devices/vsource.sym} 2370 -1600 0 0 {name=V_isnk1 value=0 savecurrent=true}
C {JNW_ATR_SKY130A/JNWATR_PCH_2C5F0.sym} 2510 -2630 0 0 {name=x65 }
C {devices/vsource.sym} 2990 -2440 0 0 {name=V_iPreCharge2 value=0 savecurrent=true}
C {JNW_ATR_SKY130A/JNWATR_NCH_2C1F2.sym} 3030 -2350 0 1 {name=x66 }
C {devices/lab_wire.sym} 3045 -2350 0 1 {name=p125 sig_type=std_logic lab=preChrg}
C {JNW_TR_SKY130A/JNWTR_RPPO2.sym} 2990 -2580 1 0 {name=x67 }
C {JNW_TR_SKY130A/JNWTR_RPPO2.sym} 2990 -2950 1 0 {name=x68 }
C {JNW_TR_SKY130A/JNWTR_RPPO2.sym} 2990 -3060 1 0 {name=x69 }
C {JNW_TR_SKY130A/JNWTR_RPPO2.sym} 2990 -2840 1 0 {name=x70 }
C {devices/vsource.sym} 2370 -1950 0 0 {name=V_isnk_drain1 value=0 savecurrent=true}
C {devices/vsource.sym} 2370 -2380 0 0 {name=V_isrc_source1 value=0 savecurrent=true}
C {devices/lab_wire.sym} 2515 -1910 0 1 {name=p126 sig_type=std_logic lab=vdd}
C {devices/vsource.sym} 2710 -2370 0 0 {name=V_icap_bot1 value=0 savecurrent=true}
C {devices/vsource.sym} 2780 -1800 0 0 {name=V_iprecharge3 value=0 savecurrent=true}
C {devices/vsource.sym} 2890 -2050 1 0 {name=V_ipmosGate1 value=0 savecurrent=true}
C {devices/vsource.sym} 2710 -2600 0 0 {name=V_icap_top1 value=0 savecurrent=true}
C {devices/lab_wire.sym} 2765 -1740 0 0 {name=p127 sig_type=std_logic lab=vss}
C {JNW_TR_SKY130A/JNWTR_RPPO2.sym} 2990 -2730 1 0 {name=x72 }
C {JNW_TR_SKY130A/JNWTR_RPPO2.sym} 3020 -2580 1 0 {name=x73 }
C {devices/ipin.sym} 1440 -2440 0 0 {name=p128 lab=snk
}
C {devices/ipin.sym} 1440 -2460 0 0 {name=p129 lab=src_n}
C {devices/lab_wire.sym} 2315 -2240 0 0 {name=p132 sig_type=std_logic lab=src_gate_n}
C {devices/lab_wire.sym} 2315 -1860 0 0 {name=p133 sig_type=std_logic lab=snk_gate}
C {devices/vsource.sym} 2780 -1570 0 0 {name=V_iPreCharge6 value=410m savecurrent=true}
C {devices/lab_wire.sym} 2785 -1480 0 1 {name=p155 sig_type=std_logic lab=vss}
C {devices/ipin.sym} 1490 -2050 0 0 {name=p156 lab=cmp}
C {devices/lab_wire.sym} 1985 -2240 0 1 {name=p157 sig_type=std_logic lab=src_gate}
C {JNW_TR_SKY130A/JNWTR_IVX1_CV.sym} 2110 -2240 0 0 {name=x85 }
C {devices/lab_wire.sym} 2165 -2280 0 1 {name=p158 sig_type=std_logic lab=vdd}
C {devices/lab_wire.sym} 2145 -2200 0 0 {name=p159 sig_type=std_logic lab=vss}
C {devices/lab_wire.sym} 1995 -1860 0 1 {name=p160 sig_type=std_logic lab=snk_gate_n}
C {JNW_TR_SKY130A/JNWTR_TGX2_CV.sym} 1680 -2240 0 0 {name=x86 }
C {devices/lab_wire.sym} 1770 -2280 0 1 {name=p161 sig_type=std_logic lab=vdd

}
C {devices/lab_wire.sym} 1770 -2190 0 1 {name=p162 sig_type=std_logic lab=vss

}
C {devices/lab_wire.sym} 1740 -2300 0 0 {name=p163 sig_type=std_logic lab=src_n

}
C {devices/lab_wire.sym} 1870 -1970 0 1 {name=p164 sig_type=std_logic lab=vdd

}
C {JNW_TR_SKY130A/JNWTR_TGX2_CV.sym} 1690 -1860 0 0 {name=x87 }
C {devices/lab_wire.sym} 1780 -1900 0 1 {name=p165 sig_type=std_logic lab=vdd

}
C {devices/lab_wire.sym} 1780 -1810 0 1 {name=p166 sig_type=std_logic lab=vss

}
C {devices/lab_wire.sym} 1750 -1920 0 0 {name=p167 sig_type=std_logic lab=snk

}
C {JNW_ATR_SKY130A/JNWATR_PCH_2C1F2.sym} 1830 -1920 0 0 {name=x88 }
C {JNW_TR_SKY130A/JNWTR_IVX1_CV.sym} 2170 -1860 0 0 {name=x89 }
C {devices/lab_wire.sym} 2210 -1820 0 1 {name=p168 sig_type=std_logic lab=vss

}
C {devices/lab_wire.sym} 2210 -1900 0 1 {name=p169 sig_type=std_logic lab=vdd

}
C {JNW_ATR_SKY130A/JNWATR_NCH_2C1F2.sym} 2040 -2130 0 0 {name=x90 }
C {devices/lab_wire.sym} 2080 -2100 0 1 {name=p170 sig_type=std_logic lab=vss

}
C {JNW_TR_SKY130A/JNWTR_IVX1_CV.sym} 1930 -2130 0 0 {name=x91 }
C {devices/lab_wire.sym} 1970 -2090 0 1 {name=p171 sig_type=std_logic lab=vss

}
C {devices/lab_wire.sym} 1970 -2170 0 1 {name=p172 sig_type=std_logic lab=vdd

}
C {devices/lab_wire.sym} 3720 -2610 0 0 {name=p174 sig_type=std_logic lab=pbias}
C {devices/lab_wire.sym} 3550 -3050 0 1 {name=p175 sig_type=std_logic lab=vdd}
C {devices/lab_wire.sym} 3640 -2210 0 1 {name=p176 sig_type=std_logic lab=vss}
C {JNW_ATR_SKY130A/JNWATR_NCH_2C5F0.sym} 3590 -2260 0 1 {name=x28[6:0]}
C {devices/lab_wire.sym} 3760 -2730 0 0 {name=p177 sig_type=std_logic lab=vdd}
C {JNW_ATR_SKY130A/JNWATR_NCH_2C5F0.sym} 3720 -2260 0 0 {name=x92 }
C {devices/lab_wire.sym} 3700 -2260 0 0 {name=p178 sig_type=std_logic lab=nbias}
C {devices/vsource.sym} 3550 -2360 0 0 {name=v_nbias value=0 savecurrent=true}
C {devices/vsource.sym} 3760 -2550 0 0 {name=v_pbias value=0 savecurrent=true}
C {JNW_TR_SKY130A/JNWTR_RPPO16.sym} 3550 -2850 1 1 {name=x93 }
C {JNW_TR_SKY130A/JNWTR_RPPO16.sym} 3550 -2930 1 1 {name=x94 }
C {JNW_ATR_SKY130A/JNWATR_PCH_2C5F0.sym} 3720 -2670 0 0 {name=x95 }
C {JNW_TR_SKY130A/JNWTR_RPPO16.sym} 3550 -2770 1 1 {name=x96 }
C {JNW_ATR_SKY130A/JNWATR_NCH_2C5F0.sym} 3590 -2510 0 1 {name=x97 }
C {devices/lab_wire.sym} 2490 -2630 0 0 {name=p180 sig_type=std_logic lab=pbias}
C {devices/lab_wire.sym} 2320 -1520 0 0 {name=p181 sig_type=std_logic lab=nbias}
C {devices/lab_wire.sym} 3610 -2570 0 0 {name=p182 sig_type=std_logic lab=ncasc}
C {devices/lab_wire.sym} 2780 -1670 0 1 {name=p49 sig_type=std_logic lab=Vpre

}
C {devices/lab_wire.sym} 1930 -2130 0 0 {name=p50 sig_type=std_logic lab=src_n

}
C {devices/vsource.sym} 2370 -2110 0 0 {name=V_isrc_drain value=0 savecurrent=true}
C {JNW_ATR_SKY130A/JNWATR_NCH_2C5F0.sym} 2820 -1740 0 1 {name=x14 }
